VERSION 5.7 ;
NOWIREEXTENSIONATPIN ON ;
DIVIDERCHAR "/" ;
BUSBITCHARS "[]" ;
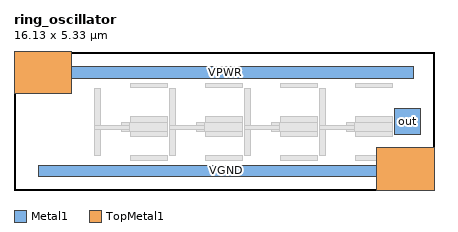
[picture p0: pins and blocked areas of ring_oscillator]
MACRO ring_oscillator
  CLASS BLOCK ;
  FOREIGN ring_oscillator 0.000 0.000 ;
  ORIGIN 0.000 0.000 ;
  SIZE 16.130 BY 5.330 ;
  PIN out
    DIRECTION OUTPUT ;
    USE SIGNAL ;
    PORT
      LAYER Metal1 ;
        RECT 14.625 2.130 15.625 3.130 ;
    END
  END out
  PIN VPWR
    DIRECTION INOUT ;
    USE POWER ;
    PORT
      LAYER Metal1 ;
        RECT 0.930 4.290 15.330 4.730 ;
      LAYER TopMetal1 ;
        RECT 0.000 3.690 2.200 5.330 ;
    END
  END VPWR
  PIN VGND
    DIRECTION INOUT ;
    USE GROUND ;
    PORT
      LAYER Metal1 ;
        RECT 0.930 0.510 15.330 0.950 ;
      LAYER TopMetal1 ;
        RECT 13.930 0.000 16.130 1.640 ;
    END
  END VGND
  OBS
      LAYER GatPoly ;
        RECT 4.460 3.925 5.910 4.105 ;
        RECT 7.340 3.925 8.790 4.105 ;
        RECT 10.220 3.925 11.670 4.105 ;
        RECT 13.100 3.925 14.550 4.105 ;
        RECT 4.460 2.580 5.910 2.805 ;
        RECT 7.340 2.580 8.790 2.805 ;
        RECT 10.220 2.580 11.670 2.805 ;
        RECT 13.100 2.580 14.550 2.805 ;
        RECT 4.120 2.250 5.910 2.580 ;
        RECT 7.000 2.250 8.790 2.580 ;
        RECT 9.880 2.250 11.670 2.580 ;
        RECT 12.760 2.250 14.550 2.580 ;
        RECT 4.460 2.060 5.910 2.250 ;
        RECT 7.340 2.060 8.790 2.250 ;
        RECT 10.220 2.060 11.670 2.250 ;
        RECT 13.100 2.060 14.550 2.250 ;
        RECT 4.460 1.140 5.910 1.320 ;
        RECT 7.340 1.140 8.790 1.320 ;
        RECT 10.220 1.140 11.670 1.320 ;
        RECT 13.100 1.140 14.550 1.320 ;
      LAYER Metal1 ;
        RECT 3.105 2.495 3.335 3.905 ;
        RECT 4.120 2.495 4.435 2.580 ;
        RECT 3.105 2.335 4.435 2.495 ;
        RECT 3.105 1.340 3.335 2.335 ;
        RECT 4.120 2.250 4.435 2.335 ;
        RECT 5.985 2.495 6.215 3.905 ;
        RECT 7.000 2.495 7.315 2.580 ;
        RECT 5.985 2.335 7.315 2.495 ;
        RECT 5.985 1.340 6.215 2.335 ;
        RECT 7.000 2.250 7.315 2.335 ;
        RECT 8.865 2.495 9.095 3.905 ;
        RECT 9.880 2.495 10.195 2.580 ;
        RECT 8.865 2.335 10.195 2.495 ;
        RECT 8.865 1.340 9.095 2.335 ;
        RECT 9.880 2.250 10.195 2.335 ;
        RECT 11.745 2.495 11.975 3.905 ;
        RECT 12.760 2.495 13.075 2.580 ;
        RECT 11.745 2.335 13.075 2.495 ;
        RECT 11.745 1.340 11.975 2.335 ;
        RECT 12.760 2.250 13.075 2.335 ;
      LAYER Metal2 ;
        RECT 0.000 4.400 1.300 4.800 ;
        RECT 14.830 0.530 16.130 0.930 ;
      LAYER Metal3 ;
        RECT 0.000 4.400 1.300 4.800 ;
        RECT 14.830 0.530 16.130 0.930 ;
      LAYER Metal4 ;
        RECT 0.000 4.400 1.300 4.800 ;
        RECT 14.830 0.530 16.130 0.930 ;
      LAYER Metal5 ;
        RECT 0.000 4.190 1.510 5.010 ;
        RECT 14.620 0.320 16.130 1.140 ;
  END
END ring_oscillator
END LIBRARY
